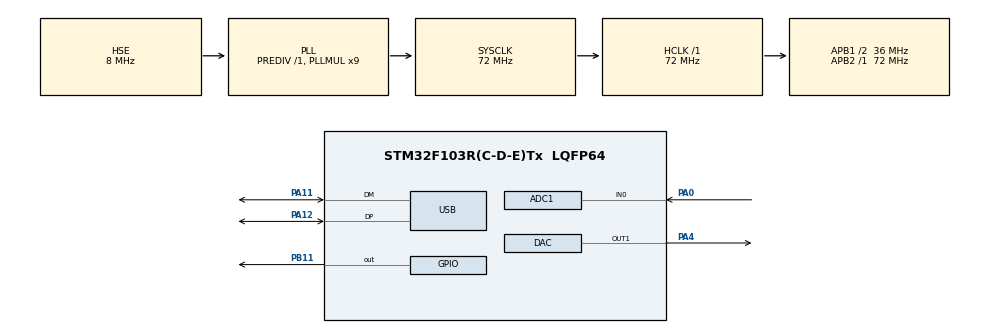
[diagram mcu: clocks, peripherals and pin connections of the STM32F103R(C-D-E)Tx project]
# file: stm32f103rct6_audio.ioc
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ADC1.Channel-0\#ChannelRegularConversion=ADC_CHANNEL_0
ADC1.ExternalTrigConv=ADC_EXTERNALTRIGCONV_T1_CC1
ADC1.NbrOfConversionFlag=1
ADC1.Rank-0\#ChannelRegularConversion=1
ADC1.SamplingTime-0\#ChannelRegularConversion=ADC_SAMPLETIME_1CYCLE_5
ADC1.master=1
DAC.DAC_Trigger=DAC_TRIGGER_T2_TRGO
Dma.ADC1.0.Direction=DMA_PERIPH_TO_MEMORY
Dma.ADC1.0.Instance=DMA1_Channel1
Dma.ADC1.0.MemDataAlignment=DMA_MDATAALIGN_HALFWORD
Dma.ADC1.0.MemInc=DMA_MINC_ENABLE
Dma.ADC1.0.Mode=DMA_CIRCULAR
Dma.ADC1.0.PeriphDataAlignment=DMA_PDATAALIGN_HALFWORD
Dma.ADC1.0.PeriphInc=DMA_PINC_DISABLE
Dma.ADC1.0.Priority=DMA_PRIORITY_LOW
Dma.DAC_CH1.1.Direction=DMA_MEMORY_TO_PERIPH
Dma.DAC_CH1.1.Instance=DMA2_Channel3
Dma.DAC_CH1.1.MemDataAlignment=DMA_MDATAALIGN_HALFWORD
Dma.DAC_CH1.1.MemInc=DMA_MINC_ENABLE
Dma.DAC_CH1.1.Mode=DMA_NORMAL
Dma.DAC_CH1.1.PeriphDataAlignment=DMA_PDATAALIGN_HALFWORD
Dma.DAC_CH1.1.PeriphInc=DMA_PINC_DISABLE
Dma.DAC_CH1.1.Priority=DMA_PRIORITY_LOW
Dma.Request0=ADC1
Dma.Request1=DAC_CH1
Mcu.Family=STM32F1
Mcu.Name=STM32F103R(C-D-E)Tx
Mcu.Package=LQFP64
NVIC.DMA1_Channel1_IRQn=true\:0\:0\:false\:false\:true\:false
NVIC.DMA2_Channel3_IRQn=true\:0\:0\:false\:false\:true\:false
NVIC.PriorityGroup=NVIC_PRIORITYGROUP_4
NVIC.USB_LP_CAN1_RX0_IRQn=true\:0\:0\:false\:false\:true\:false
PA0-WKUP.Signal=ADCx_IN0
PA11.Mode=Device
PA11.Signal=USB_DM
PA12.Mode=Device
PA12.Signal=USB_DP
PA13.Mode=Serial_Wire
PA13.Signal=SYS_JTMS-SWDIO
PA14.Mode=Serial_Wire
PA14.Signal=SYS_JTCK-SWCLK
PA4.Signal=COMP_DAC1_group
PB11.Signal=GPIO_Output
PC14-OSC32_IN.Mode=LSE-External-Oscillator
PC14-OSC32_IN.Signal=RCC_OSC32_IN
PC15-OSC32_OUT.Mode=LSE-External-Oscillator
PC15-OSC32_OUT.Signal=RCC_OSC32_OUT
PD0-OSC_IN.Mode=HSE-External-Oscillator
PD0-OSC_IN.Signal=RCC_OSC_IN
PD1-OSC_OUT.Mode=HSE-External-Oscillator
PD1-OSC_OUT.Signal=RCC_OSC_OUT
ProjectManager.HeapSize=0x200
ProjectManager.StackSize=0x400
ProjectManager.TargetToolchain=Makefile
RCC.ADCPresc=RCC_ADCPCLK2_DIV6
RCC.AHBFreq_Value=72000000
RCC.APB1CLKDivider=RCC_HCLK_DIV2
RCC.APB1Freq_Value=36000000
RCC.APB1TimFreq_Value=72000000
RCC.APB2Freq_Value=72000000
RCC.APB2TimFreq_Value=72000000
RCC.HCLKFreq_Value=72000000
RCC.PLLMUL=RCC_PLL_MUL9
RCC.SYSCLKFreq_VALUE=72000000
RCC.SYSCLKSource=RCC_SYSCLKSOURCE_PLLCLK
RCC.USBFreq_Value=48000000
RCC.USBPrescaler=RCC_USBCLKSOURCE_PLL_DIV1_5
SH.ADCx_IN0.0=ADC1_IN0,IN0
SH.COMP_DAC1_group.0=DAC_OUT1,DAC_OUT1
TIM1.Channel-PWM\ Generation1\ No\ Output=TIM_CHANNEL_1
TIM1.Period=(72000000 / 128000) -1
TIM2.Period=(72000000 / 128000) -1
TIM2.TIM_MasterOutputTrigger=TIM_TRGO_UPDATE
USB_DEVICE.CLASS_NAME_FS=CDC
USB_DEVICE.VirtualMode=Cdc
USB_DEVICE.VirtualModeFS=Cdc_FS
VP_TIM1_VS_ClockSourceINT.Mode=Internal
VP_TIM1_VS_no_output1.Mode=PWM Generation1 No Output
VP_TIM2_VS_ClockSourceINT.Mode=Internal
VP_USB_DEVICE_VS_USB_DEVICE_CDC_FS.Mode=CDC_FS
board=custom

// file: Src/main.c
/**
  ******************************************************************************
  * @file           : main.c
  * @brief          : Main program body
  ******************************************************************************
  * This notice applies to any and all portions of this file
  * that are not between comment pairs USER CODE BEGIN and
  * USER CODE END. Other portions of this file, whether
  * inserted by the user or by software development tools
  * are owned by their respective copyright owners.
  *
  * Copyright (c) 2018 STMicroelectronics International N.V.
  * All rights reserved.
  *
  * Redistribution and use in source and binary forms, with or without
  * modification, are permitted, provided that the following conditions are met:
  *
  * 1. Redistribution of source code must retain the above copyright notice,
  *    this list of conditions and the following disclaimer.
  * 2. Redistributions in binary form must reproduce the above copyright notice,
  *    this list of conditions and the following disclaimer in the documentation
  *    and/or other materials provided with the distribution.
  * 3. Neither the name of STMicroelectronics nor the names of other
  *    contributors to this software may be used to endorse or promote products
  *    derived from this software without specific written permission.
  * 4. This software, including modifications and/or derivative works of this
  *    software, must execute solely and exclusively on microcontroller or
  *    microprocessor devices manufactured by or for STMicroelectronics.
  * 5. Redistribution and use of this software other than as permitted under
  *    this license is void and will automatically terminate your rights under
  *    this license.
  *
  * THIS SOFTWARE IS PROVIDED BY STMICROELECTRONICS AND CONTRIBUTORS "AS IS"
  * AND ANY EXPRESS, IMPLIED OR STATUTORY WARRANTIES, INCLUDING, BUT NOT
  * LIMITED TO, THE IMPLIED WARRANTIES OF MERCHANTABILITY, FITNESS FOR A
  * PARTICULAR PURPOSE AND NON-INFRINGEMENT OF THIRD PARTY INTELLECTUAL PROPERTY
  * RIGHTS ARE DISCLAIMED TO THE FULLEST EXTENT PERMITTED BY LAW. IN NO EVENT
  * SHALL STMICROELECTRONICS OR CONTRIBUTORS BE LIABLE FOR ANY DIRECT, INDIRECT,
  * INCIDENTAL, SPECIAL, EXEMPLARY, OR CONSEQUENTIAL DAMAGES (INCLUDING, BUT NOT
  * LIMITED TO, PROCUREMENT OF SUBSTITUTE GOODS OR SERVICES; LOSS OF USE, DATA,
  * OR PROFITS; OR BUSINESS INTERRUPTION) HOWEVER CAUSED AND ON ANY THEORY OF
  * LIABILITY, WHETHER IN CONTRACT, STRICT LIABILITY, OR TORT (INCLUDING
  * NEGLIGENCE OR OTHERWISE) ARISING IN ANY WAY OUT OF THE USE OF THIS SOFTWARE,
  * EVEN IF ADVISED OF THE POSSIBILITY OF SUCH DAMAGE.
  *
  ******************************************************************************
  */
#include "main.h"
#include "stm32f1xx_hal.h"
#include "adc.h"
#include "dac.h"
#include "dma.h"
#include "tim.h"
#include "usb_device.h"
#include "gpio.h"

/* USER CODE BEGIN Includes */
#include "app.h"

/* USER CODE END Includes */

/* USER CODE BEGIN PV */
/* Private variables ---------------------------------------------------------*/

/* USER CODE END PV */

void SystemClock_Config(void);

/* USER CODE BEGIN PFP */
/* Private function prototypes -----------------------------------------------*/

/* USER CODE END PFP */

int main(void)
{

  /* MCU Configuration----------------------------------------------------------*/

  /* Reset of all peripherals, Initializes the Flash interface and the Systick. */
  HAL_Init();

  /* USER CODE BEGIN Init */
  app_init_f();
  /* USER CODE END Init */

  /* Configure the system clock */
  SystemClock_Config();

  /* Initialize all configured peripherals */
  MX_GPIO_Init();
  MX_DMA_Init();
  MX_USB_DEVICE_Init();
  MX_ADC1_Init();
  MX_TIM1_Init();
  MX_DAC_Init();
  MX_TIM2_Init();
  /* USER CODE BEGIN 2 */
  app_init();
  app_start();
  /* USER CODE END 2 */

  /* Infinite loop */
  /* USER CODE BEGIN WHILE */
  app_loop();
  /* USER CODE END WHILE */

}

void SystemClock_Config(void)
{

  RCC_OscInitTypeDef RCC_OscInitStruct;
  RCC_ClkInitTypeDef RCC_ClkInitStruct;
  RCC_PeriphCLKInitTypeDef PeriphClkInit;

    /**Initializes the CPU, AHB and APB busses clocks
    */
  RCC_OscInitStruct.OscillatorType = RCC_OSCILLATORTYPE_HSE;
  RCC_OscInitStruct.HSEState = RCC_HSE_ON;
  RCC_OscInitStruct.HSEPredivValue = RCC_HSE_PREDIV_DIV1;
  RCC_OscInitStruct.HSIState = RCC_HSI_ON;
  RCC_OscInitStruct.PLL.PLLState = RCC_PLL_ON;
  RCC_OscInitStruct.PLL.PLLSource = RCC_PLLSOURCE_HSE;
  RCC_OscInitStruct.PLL.PLLMUL = RCC_PLL_MUL9;
  if (HAL_RCC_OscConfig(&RCC_OscInitStruct) != HAL_OK)
  {
    _Error_Handler(__FILE__, __LINE__);
  }

    /**Initializes the CPU, AHB and APB busses clocks
    */
  RCC_ClkInitStruct.ClockType = RCC_CLOCKTYPE_HCLK|RCC_CLOCKTYPE_SYSCLK
                              |RCC_CLOCKTYPE_PCLK1|RCC_CLOCKTYPE_PCLK2;
  RCC_ClkInitStruct.SYSCLKSource = RCC_SYSCLKSOURCE_PLLCLK;
  RCC_ClkInitStruct.AHBCLKDivider = RCC_SYSCLK_DIV1;
  RCC_ClkInitStruct.APB1CLKDivider = RCC_HCLK_DIV2;
  RCC_ClkInitStruct.APB2CLKDivider = RCC_HCLK_DIV1;

  if (HAL_RCC_ClockConfig(&RCC_ClkInitStruct, FLASH_LATENCY_2) != HAL_OK)
  {
    _Error_Handler(__FILE__, __LINE__);
  }

  PeriphClkInit.PeriphClockSelection = RCC_PERIPHCLK_ADC|RCC_PERIPHCLK_USB;
  PeriphClkInit.AdcClockSelection = RCC_ADCPCLK2_DIV6;
  PeriphClkInit.UsbClockSelection = RCC_USBCLKSOURCE_PLL_DIV1_5;
  if (HAL_RCCEx_PeriphCLKConfig(&PeriphClkInit) != HAL_OK)
  {
    _Error_Handler(__FILE__, __LINE__);
  }

    /**Configure the Systick interrupt time
    */
  HAL_SYSTICK_Config(HAL_RCC_GetHCLKFreq()/1000);

    /**Configure the Systick
    */
  HAL_SYSTICK_CLKSourceConfig(SYSTICK_CLKSOURCE_HCLK);

  /* SysTick_IRQn interrupt configuration */
  HAL_NVIC_SetPriority(SysTick_IRQn, 0, 0);
}

void _Error_Handler(char *file, int line)
{
  while(1)
  {
  }
}

/************************ (C) COPYRIGHT STMicroelectronics *****END OF FILE****/
